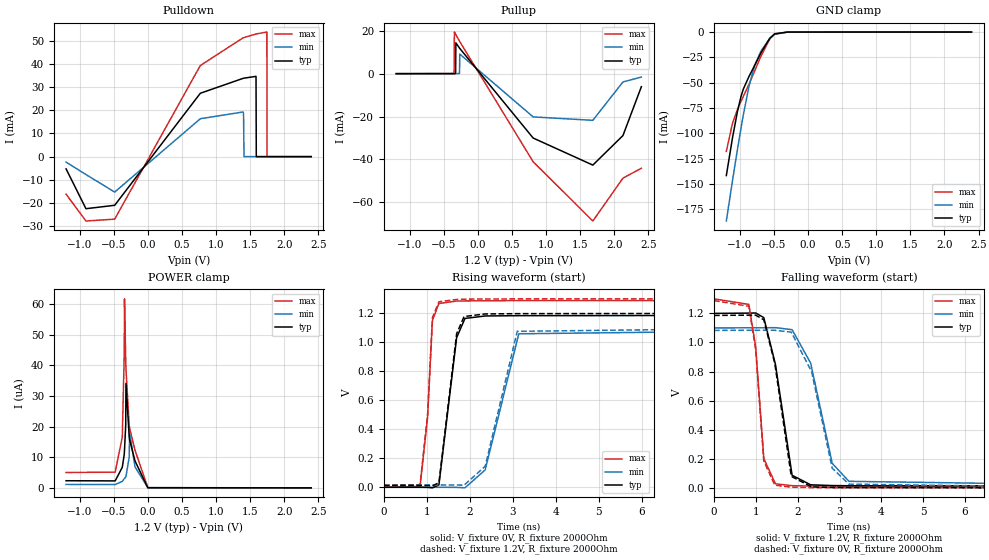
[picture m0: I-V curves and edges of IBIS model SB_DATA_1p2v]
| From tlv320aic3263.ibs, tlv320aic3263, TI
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|   SB_DATA_1p2v
[Model]   SB_DATA_1p2v
Model_type   I/O
Polarity   Non-Inverting
Enable   Active-Low
Vinl = 0.12
Vinh = 1.08
Vmeas = 0.6
Vref = 1.2
Cref = 1pF
Rref = 2000
|   typ   min   max
C_comp   0.971pF   0.938pF   1.010pF
[Voltage Range]   1.2   1.1   1.3
[Temperature Range]   27   125   -40
[Pullup Reference]   1.2   1.1   1.3
[Pulldown Reference]   -0   -0   -0
[Power Clamp Reference]   1.2   1.1   1.3
[GND Clamp Reference]   -0   -0   -0
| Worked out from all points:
|   slope of the pulldown table from 0 to 0.18 V, typ, clamps not added: 22.5 ohm
|   slope of the pullup table from 0 to 0.18 V, typ, clamps not added: 23.8 ohm
|   GND clamp passes 1 mA (typ) near -0.46 V on its own axis
|   falling waveform, V_fixture 1.2V, R_fixture 2000Ohm: 20-80 % time 294ps typ, 478ps min, 197ps max; typ from 1.2 V to 0.013 V
|   rising waveform, V_fixture 0V, R_fixture 2000Ohm: 20-80 % time 232ps typ, 382ps min, 162ps max; typ from 0 V to 1.19 V
|   rising waveform, V_fixture 1.2V, R_fixture 2000Ohm: 20-80 % time 230ps typ, 370ps min, 163ps max; typ from 0.013 V to 1.2 V
|   falling waveform, V_fixture 0V, R_fixture 2000Ohm: 20-80 % time 294ps typ, 478ps min, 197ps max; typ from 1.19 V to 0 V
[Pulldown]
|   Voltage   I(typ)   I(min)   I(max)
-1.2V     -5.286mA   -2.37mA    -16.2mA
-908.4mV  -22.46mA   -7.727mA   -27.77mA
-487.2mV  -20.99mA   -15.29mA   -26.97mA
769.2mV   27.34mA    16.35mA    39.31mA
1.396V    33.76mA    19.27mA    51.24mA
1.403V    33.81mA    18.59mA    51.31mA
1.41V     33.86mA    -859.3nA   51.38mA
1.586V    34.63mA    1.645nA    52.9mA
1.59V     -3.127uA   1.642nA    52.93mA
1.745V    197.2pA    1.618nA    53.75mA
1.748V    197.1pA    1.618nA    -614.5nA
2.396V    305.9pA    1.888nA    30.17pA
[GND Clamp]
|   Voltage   I(typ)   I(min)   I(max)
-1.2V     -141.7mA   -186.6mA   -117.8mA
-1.11V    -104.6mA   -146.9mA   -90.22mA
-1.038V   -78.75mA   -116.3mA   -76.61mA
-984mV    -63.46mA   -94.55mA   -68.36mA
-951.6mV  -56.47mA   -82.15mA   -63.64mA
-868.8mV  -44.01mA   -53.94mA   -51.7mA
-786mV    -33.17mA   -33.23mA   -38.76mA
-692.4mV  -20.56mA   -18.79mA   -23.91mA
-562.8mV  -6.154mA   -6.26mA    -6.871mA
-490.8mV  -1.797mA   -2.277mA   -1.795mA
-300mV    -21.89uA   -35.95uA   -26.81uA
2.396V    0A         0A         0A
[Pullup]
|   Voltage   I(typ)   I(min)   I(max)
-1.2V     842.9pA    8.701nA    61.33pA
-357.6mV  4.164uA    259.4nA    104uA
-350.4mV  8.121uA    257nA      521.9uA
-346.8mV  11.56uA    266.3nA    19.42mA
-328.8mV  130.7uA    482.1nA    18.39mA
-325.2mV  14.39mA    580.8nA    18.19mA
-271.2mV  11.94mA    78.29uA    15.14mA
-267.6mV  11.78mA    9.138mA    14.94mA
808.8mV   -30.02mA   -20.17mA   -41.09mA
1.684V    -42.64mA   -21.76mA   -68.72mA
2.126V    -28.86mA   -3.859mA   -48.72mA
2.396V    -6.07mA    -1.585mA   -44.12mA
[POWER Clamp]
|   Voltage   I(typ)   I(min)   I(max)
-1.2V     2.322uA    1.118uA    5.019uA
-480mV    2.269uA    1.068uA    5.127uA
-375.6mV  6.708uA    2.108uA    16.58uA
-346.8mV  10.94uA    3.003uA    43.76uA
-343.2mV  12.32uA    3.078uA    61.73uA
-325.2mV  20.51uA    3.543uA    41.71uA
-321.6mV  34.15uA    3.679uA    38.83uA
-274.8mV  16.92uA    9.923uA    20.56uA
-267.6mV  15.65uA    17.89uA    19.39uA
-188.4mV  8.757uA    6.849uA    12.27uA
-1.2mV    43.68nA    37.44nA    66.53nA
2.396V    0A         0A         0A
[Ramp]
R_load = 2000
|   typ   min   max
dV/dt_r   0.711726/2.31825e-10   0.650025/3.82476e-10   0.772994/1.62415e-10
dV/dt_f   0.712107/2.93834e-10   0.650031/4.76288e-10   0.773381/1.97433e-10
[Falling Waveform]
V_fixture = 1.2V
V_fixture_min = 1.1V
V_fixture_max = 1.3V
R_fixture = 2000Ohm
C_fixture = 0F
|   Time   V(typ)   V(min)   V(max)
0s        1.2V       1.1V       1.3V
831.2ps   1.202V     1.101V     1.262V
993.9ps   1.203V     1.101V     971.1mV
1.189ns   1.171V     1.101V     202mV
1.467ns   849.7mV    1.102V     27.8mV
1.866ns   86.29mV    1.088V     15.01mV
2.31ns    20.9mV     857.6mV    12.36mV
2.825ns   15.71mV    168.3mV    12.27mV
3.224ns   14.64mV    44.88mV    12.2mV
10ns      13.15mV    16.61mV    11.03mV
[Rising Waveform]
V_fixture = 0V
V_fixture_min = 0V
V_fixture_max = 0V
R_fixture = 2000Ohm
C_fixture = 0F
|   Time   V(typ)   V(min)   V(max)
0s        14.18nV    317.2nV    2.937nV
840.9ps   56.1uV     16.18uV    6.209mV
1.016ns   -435.4uV   19.5uV     483.4mV
1.129ns   -3.751mV   21.63uV    1.152V
1.28ns    16.48mV    24.46uV    1.268V
1.693ns   1.033V     -521.2uV   1.285V
1.887ns   1.165V     -3.484mV   1.286V
2.358ns   1.182V     120.2mV    1.287V
3.14ns    1.184V     1.059V     1.288V
10ns      1.186V     1.083V     1.288V
[Rising Waveform]
V_fixture = 1.2V
V_fixture_min = 1.1V
V_fixture_max = 1.3V
R_fixture = 2000Ohm
C_fixture = 0F
|   Time   V(typ)   V(min)   V(max)
0s        12.91mV    16.41mV    10.85mV
840.9ps   12.94mV    16.43mV    18.17mV
1.016ns   12.56mV    16.43mV    502mV
1.129ns   10.03mV    16.44mV    1.17V
1.28ns    31.59mV    16.44mV    1.28V
1.693ns   1.06V      15.94mV    1.296V
1.866ns   1.178V     14.61mV    1.298V
2.358ns   1.196V     145.4mV    1.299V
3.104ns   1.198V     1.076V     1.3V
10ns      1.2V       1.1V       1.3V
[Falling Waveform]
|Gnd
V_fixture = 0V
V_fixture_min = 0V
V_fixture_max = 0V
R_fixture = 2000Ohm
C_fixture = 0F
|   Time   V(typ)   V(min)   V(max)
0s        1.186V     1.083V     1.288V
831.2ps   1.188V     1.084V     1.249V
993.9ps   1.188V     1.084V     952mV
1.189ns   1.156V     1.084V     184.7mV
1.451ns   856.8mV    1.084V     18.62mV
1.846ns   78.91mV    1.071V     4.131mV
2.334ns   6.476mV    797.1mV    1.454mV
2.825ns   2.627mV    135mV      666.6uV
3.224ns   1.662mV    25.43mV    629.7uV
10ns      6.089uV    43.17uV    1.937uV
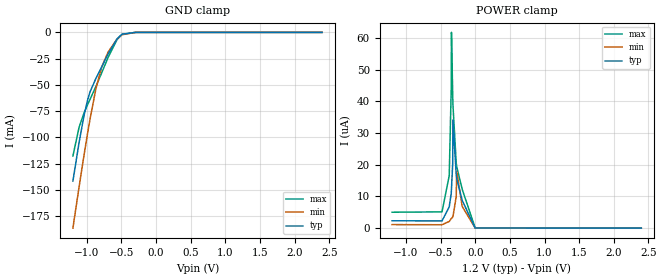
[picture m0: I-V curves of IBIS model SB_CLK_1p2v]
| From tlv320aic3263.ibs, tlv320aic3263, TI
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|   SB_CLK_1p2v
[Model]   SB_CLK_1p2v
Model_type   Input
Vinl = 0.12
Vinh = 1.08
|   typ   min   max
C_comp   0.971pF   0.938pF   1.010pF
[Voltage Range]   1.2   1.1   1.3
[Temperature Range]   27   125   -40
[Power Clamp Reference]   1.2   1.1   1.3
[GND Clamp Reference]   -0   -0   -0
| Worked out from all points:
|   GND clamp passes 1 mA (typ) near -0.46 V on its own axis
[GND Clamp]
|   Voltage   I(typ)   I(min)   I(max)
-1.2V     -141.7mA   -186.6mA   -117.8mA
-1.11V    -104.6mA   -146.9mA   -90.22mA
-1.038V   -78.75mA   -116.3mA   -76.61mA
-984mV    -63.46mA   -94.55mA   -68.36mA
-951.6mV  -56.47mA   -82.15mA   -63.64mA
-868.8mV  -44.01mA   -53.94mA   -51.7mA
-786mV    -33.17mA   -33.23mA   -38.76mA
-692.4mV  -20.56mA   -18.79mA   -23.91mA
-562.8mV  -6.154mA   -6.26mA    -6.871mA
-490.8mV  -1.797mA   -2.277mA   -1.795mA
-300mV    -21.89uA   -35.95uA   -26.81uA
2.396V    0A         0A         0A
[POWER Clamp]
|   Voltage   I(typ)   I(min)   I(max)
-1.2V     2.322uA    1.118uA    5.019uA
-480mV    2.269uA    1.068uA    5.127uA
-375.6mV  6.708uA    2.108uA    16.58uA
-346.8mV  10.94uA    3.003uA    43.76uA
-343.2mV  12.32uA    3.078uA    61.73uA
-325.2mV  20.51uA    3.543uA    41.71uA
-321.6mV  34.15uA    3.679uA    38.83uA
-274.8mV  16.92uA    9.923uA    20.56uA
-267.6mV  15.65uA    17.89uA    19.39uA
-188.4mV  8.757uA    6.849uA    12.27uA
-1.2mV    43.68nA    37.44nA    66.53nA
2.396V    0A         0A         0A
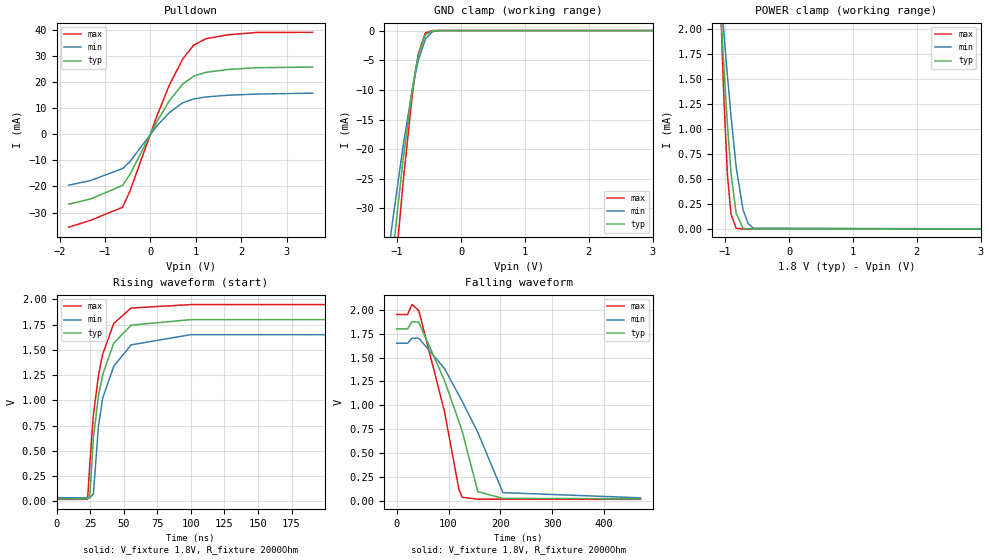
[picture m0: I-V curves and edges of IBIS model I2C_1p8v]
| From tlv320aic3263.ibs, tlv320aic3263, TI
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|   I2C_1p8v
[Model]   I2C_1p8v
Model_type   I/O_open_drain
Polarity   Non-Inverting
Enable   Active-High
Vinl = 0.54
Vinh = 1.26
Vmeas = 0.9
Vref = 0
Cref = 5pF
Rref = 2000
|   typ   min   max
C_comp   1.274pF   1.219pF   1.333pF
[Voltage Range]   1.8   1.65   1.95
[Temperature Range]   27   125   -40
[Pullup Reference]   1.8   1.65   1.95
[Pulldown Reference]   -0   -0   -0
[Power Clamp Reference]   1.8   1.65   1.95
[GND Clamp Reference]   -0   -0   -0
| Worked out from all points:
|   slope of the pulldown table from 0 to 0.27 V, typ, clamps not added: 31.1 ohm
|   GND clamp passes 1 mA (typ) near -0.57 V on its own axis
|   POWER clamp passes 1 mA (typ) near -0.96 V on its own axis
|   falling waveform, V_fixture 1.8V, R_fixture 2000Ohm: 20-80 % time 64.8ns typ, 85.6ns min, 48.8ns max; typ from 1.8 V to 0.026 V
|   rising waveform, V_fixture 1.8V, R_fixture 2000Ohm: 20-80 % time 12.4ns typ, 13.1ns min, 11.6ns max; typ from 0.026 V to 1.8 V
[Pulldown]
|   Voltage   I(typ)   I(min)   I(max)
-1.8V     -26.76mA   -19.51mA   -35.56mA
-1.314V   -24.77mA   -17.71mA   -32.93mA
-612mV    -19.57mA   -13.11mA   -27.94mA
-450mV    -15.35mA   -10.44mA   -21.73mA
144mV     4.818mA    3.184mA    7.002mA
414mV     12.69mA    8.219mA    18.67mA
711mV     19.14mA    11.99mA    28.75mA
954mV     22.19mA    13.48mA    34.04mA
1.224V    23.66mA    14.24mA    36.51mA
1.71V     24.74mA    14.9mA     38mA
2.331V    25.42mA    15.32mA    38.9mA
3.573V    25.65mA    15.7mA     38.95mA
[GND Clamp]
|   Voltage   I(typ)   I(min)   I(max)
-1.8V     -123mA     -98.92mA   -147.1mA
-1.233V   -55.18mA   -45.69mA   -66.35mA
-1.152V   -46.3mA    -38.73mA   -55.62mA
-1.071V   -37.73mA   -32.02mA   -45.21mA
-909mV    -21.87mA   -19.56mA   -25.73mA
-774mV    -10.65mA   -10.57mA   -11.84mA
-720mV    -6.977mA   -7.51mA    -7.33mA
-666mV    -3.998mA   -4.894mA   -3.785mA
-558mV    -694.3uA   -1.399mA   -419.1uA
-450mV    -48.22uA   -206.7uA   -14.05uA
-342mV    -1.744uA   -19.11uA   -162.1nA
3.573V    0A         0A         0A
[POWER Clamp]
|   Voltage   I(typ)   I(min)   I(max)
-1.8V     11.43mA    8.594mA    18.45mA
-1.098V   2.511mA    2.581mA    2.77mA
-1.071V   2.196mA    2.363mA    2.24mA
-1.044V   1.888mA    2.148mA    1.734mA
-1.017V   1.589mA    1.937mA    1.267mA
-963mV    1.031mA    1.525mA    530.8uA
-909mV    565.4uA    1.135mA    151.2uA
-828mV    156.4uA    622.8uA    6.725uA
-720mV    7.866uA    192.4uA    28.68nA
-639mV    432nA      52.31uA    0A
-558mV    5.887nA    8.012uA    0A
3.573V    0A         0A         0A
[Ramp]
R_load = 2000
|   typ   min   max
dV/dt_r   1.06459/1.23354e-008  0.968864/1.30945e-008   1.15843/1.1561e-008
dV/dt_f   1.06459/6.47139e-008  0.968864/8.5515e-008   1.15843/4.8731e-008
[Falling Waveform]
V_fixture = 1.8V
V_fixture_min = 1.65V
V_fixture_max = 1.95V
R_fixture = 2000Ohm
C_fixture = 0F
|   Time   V(typ)   V(min)   V(max)
0s        1.8V       1.65V      1.95V
21.06ns   1.799V     1.649V     1.949V
29.6ns    1.876V     1.703V     2.054V
42.59ns   1.869V     1.703V     1.991V
92.22ns   1.261V     1.385V     936.7mV
120.2ns   828.1mV    1.105V     118mV
126.3ns   729.9mV    1.042V     40.5mV
156.5ns   98.7mV     718.1mV    21.23mV
204.8ns   28.65mV    89.11mV    20.25mV
470ns     25.68mV    35.22mV    19.28mV
[Rising Waveform]
V_fixture = 1.8V
V_fixture_min = 1.65V
V_fixture_max = 1.95V
R_fixture = 2000Ohm
C_fixture = 0F
|   Time   V(typ)   V(min)   V(max)
0s        25.68mV    35.22mV    19.28mV
23.12ns   24.01mV    33.84mV    19.94mV
24.75ns   45.72mV    33.74mV    365.4mV
27.45ns   626.7mV    72.84mV    855.9mV
31.18ns   1.039V     741.1mV    1.243V
34.36ns   1.254V     1.021V     1.457V
42.59ns   1.567V     1.338V     1.762V
55.51ns   1.745V     1.55V      1.915V
99.87ns   1.8V       1.651V     1.949V
470ns     1.8V       1.65V      1.95V
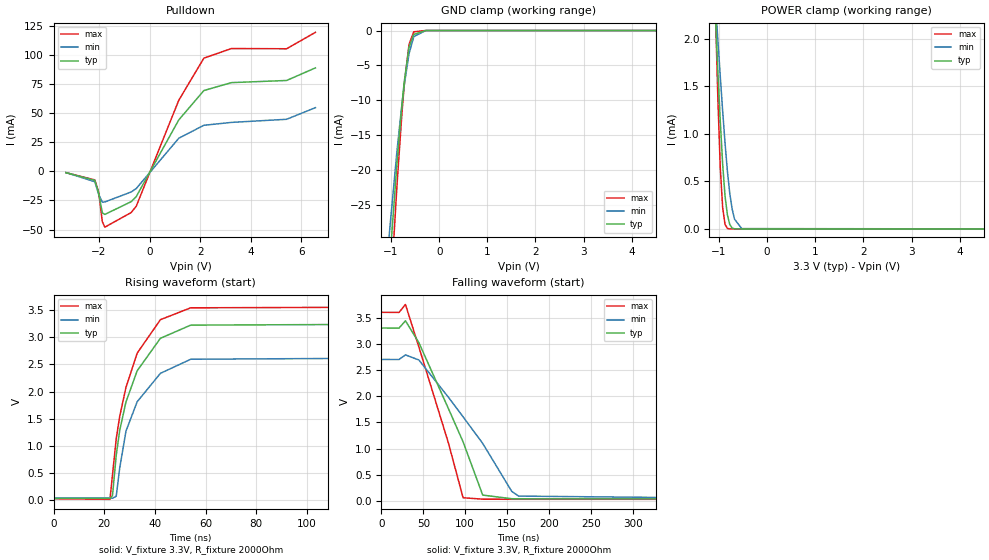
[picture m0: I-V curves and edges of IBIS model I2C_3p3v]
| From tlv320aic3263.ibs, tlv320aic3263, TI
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|   I2C_3p3v
[Model]   I2C_3p3v
Model_type   I/O_open_drain
Polarity   Non-Inverting
Enable   Active-High
Vinl = 0.8
Vinh = 2
Vmeas = 1.65
Vref = 0
Cref = 5pF
Rref = 2000
|   typ   min   max
C_comp   1.274pF   1.219pF   1.333pF
[Voltage Range]   3.3   2.7   3.6
[Temperature Range]   27   125   -40
[Pullup Reference]   3.3   2.7   3.6
[Pulldown Reference]   -0   -0   -0
[Power Clamp Reference]   3.3   2.7   3.6
[GND Clamp Reference]   -0   -0   -0
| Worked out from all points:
|   slope of the pulldown table from 0 to 0.495 V, typ, clamps not added: 24.4 ohm
|   GND clamp passes 1 mA (typ) near -0.57 V on its own axis
|   POWER clamp passes 1 mA (typ) near -0.96 V on its own axis
|   falling waveform, V_fixture 3.3V, R_fixture 2000Ohm: 20-80 % time 53.2ns typ, 71.6ns min, 40.6ns max; typ from 3.3 V to 0.038 V
|   rising waveform, V_fixture 3.3V, R_fixture 2000Ohm: 20-80 % time 11.5ns typ, 12.3ns min, 11.1ns max; typ from 0.038 V to 3.3 V
[Pulldown]
|   Voltage   I(typ)   I(min)   I(max)
-3.3V     -1.128mA   -1.068mA   -1.157mA
-2.162V   -7.775mA   -8.929mA   -7.348mA
-2.013V   -18.36mA   -19.59mA   -17.66mA
-1.865V   -35.63mA   -26.39mA   -43.24mA
-1.766V   -36.94mA   -26.26mA   -47.87mA
-726mV    -26.01mA   -17.71mA   -35.35mA
-528mV    -21.74mA   -14.81mA   -30.03mA
1.155V    44.12mA    28.4mA     60.99mA
2.145V    69.28mA    39.48mA    97.06mA
3.234V    76.07mA    41.96mA    105.3mA
5.412V    77.91mA    44.63mA    105.1mA
6.551V    88.71mA    54.61mA    119.2mA
[GND Clamp]
|   Voltage   I(typ)   I(min)   I(max)
-3.3V     -783.3mA   -712.9mA   -836mA
-1.221V   -53.85mA   -44.64mA   -64.75mA
-1.171V   -48.41mA   -40.38mA   -58.18mA
-1.122V   -43.08mA   -36.21mA   -51.73mA
-1.023V   -32.83mA   -28.18mA   -39.22mA
-874.5mV  -18.78mA   -17.11mA   -21.92mA
-775.5mV  -10.76mA   -10.66mA   -11.97mA
-726mV    -7.354mA   -7.83mA    -7.79mA
-627mV    -2.378mA   -3.342mA   -1.991mA
-528mV    -565.5uA   -877.2uA   -182.1uA
-280.5mV  -187.7nA   -4.182uA   -38.58nA
6.551V    0A         0A         0A
[POWER Clamp]
|   Voltage   I(typ)   I(min)   I(max)
-3.3V     31.29mA    21.97mA    53.42mA
-1.073V   2.213mA    2.375mA    2.269mA
-1.023V   1.654mA    1.983mA    1.366mA
-973.5mV  1.134mA    1.603mA    646.3uA
-924mV    681.5uA    1.24mA     225.7uA
-874.5mV  346.9uA    902.8uA    47.92uA
-825mV    147.4uA    606.3uA    5.86uA
-775.5mV  45.48uA    371.3uA    578.7nA
-726mV    9.636uA    207.9uA    29.35nA
-676.5mV  1.686uA    102.5uA    14.68nA
-528mV    8.133nA    3.647uA    0A
6.551V    0A         0A         0A
[Ramp]
R_load = 2000
|   typ   min   max
dV/dt_r   1.9571/1.15492e-008   1.59273/1.22255e-008   2.14173/1.105e-008
dV/dt_f   1.9571/5.32399e-008   1.59274/7.15891e-008   2.14173/4.06284e-008
[Falling Waveform]
V_fixture = 3.3V
V_fixture_min = 2.7V
V_fixture_max = 3.6V
R_fixture = 2000Ohm
C_fixture = 0F
|   Time   V(typ)   V(min)   V(max)
0s        3.3V       2.7V       3.6V
20.96ns   3.298V     2.699V     3.598V
28.68ns   3.438V     2.787V     3.749V
44.73ns   3.019V     2.69V      2.936V
80.05ns   1.759V     1.977V     1.101V
97.47ns   1.128V     1.605V     61.17mV
120.9ns   111.4mV    1.098V     33.15mV
155.5ns   42.17mV    183.7mV    31.33mV
163.8ns   39.98mV    91.97mV    31.3mV
470ns     38.17mV    45.43mV    30.45mV
[Rising Waveform]
V_fixture = 3.3V
V_fixture_min = 2.7V
V_fixture_max = 3.6V
R_fixture = 2000Ohm
C_fixture = 0F
|   Time   V(typ)   V(min)   V(max)
0s        38.17mV    45.44mV    30.45mV
22.27ns   34.67mV    45.46mV    19.49mV
23.27ns   89.11mV    39.51mV    468.8mV
24.74ns   827.4mV    76.33mV    1.132V
26.12ns   1.286V     593.8mV    1.545V
28.57ns   1.807V     1.271V     2.074V
33.01ns   2.382V     1.813V     2.706V
42.18ns   2.979V     2.335V     3.321V
54.14ns   3.221V     2.594V     3.539V
470ns     3.3V       2.7V       3.6V
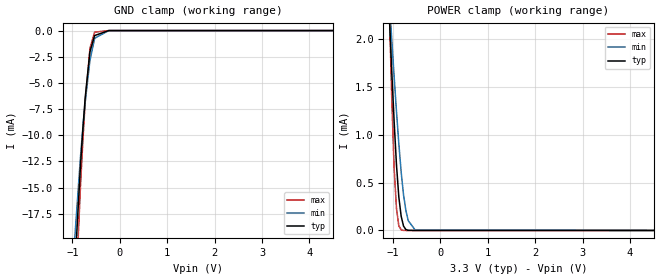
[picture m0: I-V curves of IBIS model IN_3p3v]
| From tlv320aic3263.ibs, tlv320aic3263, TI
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|   IN_3p3v
[Model]   IN_3p3v
Model_type   Input
Vinl = 0.99
Vinh = 2.31
|   typ   min   max
C_comp   1.095pF   1.082pF   1.133pF
[Voltage Range]   3.3   2.7   3.6
[Temperature Range]   27   125   -40
[Power Clamp Reference]   3.3   2.7   3.6
[GND Clamp Reference]   -0   -0   -0
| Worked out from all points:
|   GND clamp passes 1 mA (typ) near -0.58 V on its own axis
|   POWER clamp passes 1 mA (typ) near -0.96 V on its own axis
[GND Clamp]
|   Voltage   I(typ)   I(min)   I(max)
-3.3V     -782.9mA   -712.4mA   -835.6mA
-1.221V   -47.87mA   -39.35mA   -57.86mA
-1.171V   -42.98mA   -35.56mA   -51.94mA
-1.122V   -38.2mA    -31.85mA   -46.12mA
-1.023V   -29.01mA   -24.71mA   -34.85mA
-825mV    -12.75mA   -11.97mA   -14.69mA
-775.5mV  -9.352mA   -9.23mA    -10.46mA
-726mV    -6.355mA   -6.753mA   -6.753mA
-627mV    -2.02mA    -2.847mA   -1.688mA
-528mV    -475.3uA   -736.7uA   -151.8uA
-231mV    -15.95nA   -946.1nA   0A
6.551V    0A         0A         0A
[POWER Clamp]
|   Voltage   I(typ)   I(min)   I(max)
-3.3V     31.29mA    21.97mA    53.42mA
-1.073V   2.213mA    2.375mA    2.269mA
-1.023V   1.654mA    1.983mA    1.366mA
-973.5mV  1.134mA    1.603mA    646.3uA
-924mV    681.5uA    1.24mA     225.7uA
-874.5mV  346.9uA    902.8uA    47.94uA
-825mV    147.4uA    606.4uA    5.88uA
-775.5mV  45.5uA     371.3uA    598.4nA
-726mV    9.656uA    207.9uA    49.07nA
-676.5mV  1.706uA    102.5uA    24.53nA
-528mV    18.19nA    3.668uA    0A
6.551V    0A         0A         0A
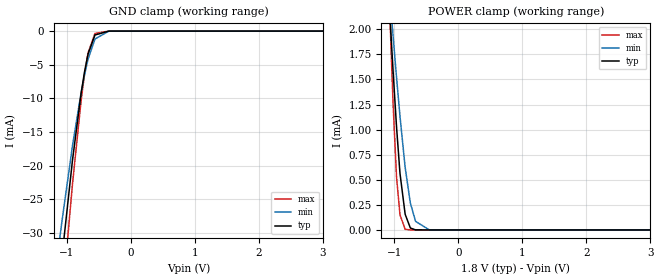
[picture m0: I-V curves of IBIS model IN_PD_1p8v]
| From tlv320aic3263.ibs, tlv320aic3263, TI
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|   IN_PD_1p8v
[Model]   IN_PD_1p8v
Model_type   Input
Vinl = 0.54
Vinh = 1.26
|   typ   min   max
C_comp   1.100pF   1.086pF   1.128pF
[Voltage Range]   1.8   1.65   1.95
[Temperature Range]   27   125   -40
[Power Clamp Reference]   1.8   1.65   1.95
[GND Clamp Reference]   -0   -0   -0
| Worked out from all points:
|   GND clamp passes 1 mA (typ) near -0.59 V on its own axis
|   POWER clamp passes 1 mA (typ) near -0.96 V on its own axis
[GND Clamp]
|   Voltage   I(typ)   I(min)   I(max)
-1.8V     -111mA     -88mA      -135mA
-1.26V    -51.79mA   -42.39mA   -62.59mA
-1.179V   -43.72mA   -36.13mA   -52.83mA
-1.125V   -38.49mA   -32.07mA   -46.46mA
-1.071V   -33.39mA   -28.12mA   -40.24mA
-909mV    -19.21mA   -17.07mA   -22.74mA
-774mV    -9.255mA   -9.15mA    -10.34mA
-720mV    -6.024mA   -6.473mA   -6.349mA
-666mV    -3.421mA   -4.192mA   -3.241mA
-558mV    -582.4uA   -1.18mA    -350.7uA
-342mV    -1.539uA   -15.95uA   -290.1nA
3.573V    0A         0A         0A
[POWER Clamp]
|   Voltage   I(typ)   I(min)   I(max)
-1.8V     11.43mA    8.594mA    18.45mA
-1.098V   2.511mA    2.581mA    2.77mA
-1.071V   2.196mA    2.363mA    2.24mA
-1.044V   1.888mA    2.148mA    1.734mA
-1.017V   1.589mA    1.937mA    1.267mA
-963mV    1.031mA    1.525mA    531.1uA
-909mV    565.5uA    1.135mA    151.4uA
-828mV    156.5uA    622.8uA    6.945uA
-747mV    19.42uA    269uA      365.4nA
-666mV    1.283uA    86.14uA    205.4nA
-450mV    100.5nA    505.3nA    201.5nA
3.573V    0A         0A         0A
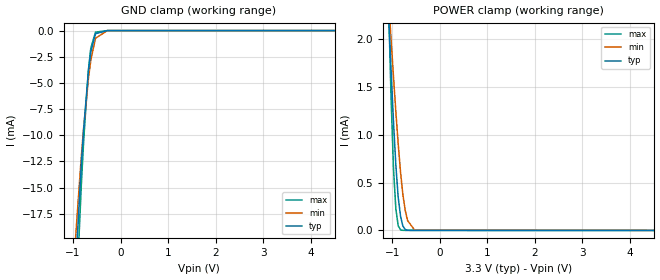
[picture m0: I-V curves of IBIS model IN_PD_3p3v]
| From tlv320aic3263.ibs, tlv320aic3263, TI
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|   EN_3p3v
[Model]   IN_PD_3p3v
Model_type   Input
Vinl = 0.99
Vinh = 2.31
|   typ   min   max
C_comp   1.100pF   1.086pF   1.128pF
[Voltage Range]   3.3   2.7   3.6
[Temperature Range]   27   125   -40
[Power Clamp Reference]   3.3   2.7   3.6
[GND Clamp Reference]   -0   -0   -0
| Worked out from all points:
|   GND clamp passes 1 mA (typ) near -0.58 V on its own axis
|   POWER clamp passes 1 mA (typ) near -0.96 V on its own axis
[GND Clamp]
|   Voltage   I(typ)   I(min)   I(max)
-3.3V     -782.9mA   -712.4mA   -835.6mA
-1.221V   -47.87mA   -39.35mA   -57.86mA
-1.171V   -42.98mA   -35.56mA   -51.94mA
-1.122V   -38.2mA    -31.85mA   -46.12mA
-1.023V   -29.01mA   -24.71mA   -34.85mA
-825mV    -12.75mA   -11.97mA   -14.69mA
-775.5mV  -9.352mA   -9.23mA    -10.46mA
-676.5mV  -3.871mA   -4.601mA   -3.763mA
-627mV    -2.02mA    -2.847mA   -1.689mA
-528mV    -299.1uA   -736.7uA   -152.2uA
-280.5mV  -280.3nA   -3.536uA   -207.1nA
6.551V    0A         0A         0A
[POWER Clamp]
|   Voltage   I(typ)   I(min)   I(max)
-3.3V     31.29mA    21.97mA    53.42mA
-1.073V   2.214mA    2.375mA    2.269mA
-1.023V   1.655mA    1.984mA    1.367mA
-973.5mV  1.134mA    1.603mA    647.2uA
-924mV    682uA      1.24mA     226.7uA
-874.5mV  347.4uA    903uA      48.91uA
-825mV    147.9uA    606.5uA    6.85uA
-775.5mV  45.99uA    371.5uA    1.57uA
-726mV    10.15uA    208.1uA    1.02uA
-676.5mV  2.201uA    102.7uA    964.5nA
-528mV    490.2nA    3.86uA     958.3nA
6.551V    0A         0A         0A
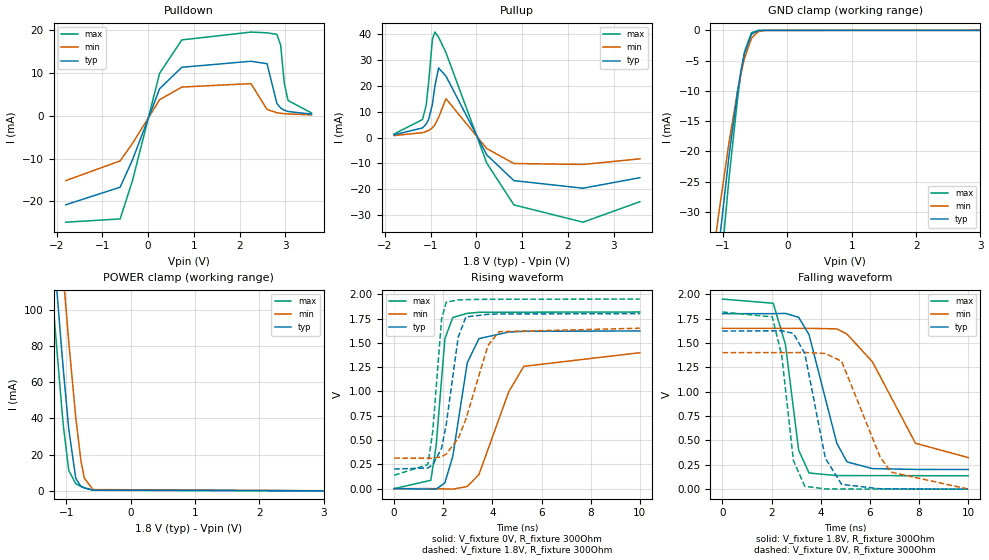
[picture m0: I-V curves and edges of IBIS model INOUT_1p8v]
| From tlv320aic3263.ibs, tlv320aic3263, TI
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|   INOUT_1p8v
[Model]   INOUT_1p8v
Model_type   I/O
Polarity   Non-Inverting
Enable   Active-High
Vinl = 0.54
Vinh = 1.26
Vmeas = 0.9
Vref = 0
Cref = 5pF
Rref = 10000
|   typ   min   max
C_comp   1.460pF   1.439pF   1.501pF
[Voltage Range]   1.8   1.65   1.95
[Temperature Range]   27   125   -40
[Pullup Reference]   1.8   1.65   1.95
[Pulldown Reference]   -0   -0   -0
[Power Clamp Reference]   1.8   1.65   1.95
[GND Clamp Reference]   -0   -0   -0
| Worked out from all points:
|   slope of the pulldown table from 0 to 0.27 V, typ, clamps not added: 40.3 ohm
|   slope of the pullup table from 0 to 0.27 V, typ, clamps not added: 34.5 ohm
|   GND clamp passes 1 mA (typ) near -0.58 V on its own axis
|   POWER clamp passes 1 mA (typ) near -0.66 V on its own axis
|   falling waveform, V_fixture 1.8V, R_fixture 300Ohm: 20-80 % time 889ps typ, 1.63ns min, 554ps max; typ from 1.8 V to 0.201 V
|   rising waveform, V_fixture 0V, R_fixture 300Ohm: 20-80 % time 598ps typ, 1.19ns min, 348ps max; typ from 0 V to 1.62 V
|   rising waveform, V_fixture 1.8V, R_fixture 300Ohm: 20-80 % time 536ps typ, 972ps min, 333ps max; typ from 0.201 V to 1.8 V
|   falling waveform, V_fixture 0V, R_fixture 300Ohm: 20-80 % time 719ps typ, 1.19ns min, 482ps max; typ from 1.62 V to 0 V
[Pulldown]
|   Voltage   I(typ)   I(min)   I(max)
-1.8V     -20.81mA   -15.15mA   -24.89mA
-612mV    -16.7mA    -10.54mA   -24.13mA
-342mV    -10.29mA   -6.449mA   -15.17mA
252mV     6.369mA    3.786mA    9.978mA
738mV     11.38mA    6.749mA    17.79mA
2.25V     12.79mA    7.557mA    19.62mA
2.601V    12.22mA    1.501mA    19.45mA
2.817V    2.895mA    733.5uA    19.08mA
2.898V    1.845mA    610.1uA    16.6mA
2.979V    1.328mA    521.1uA    7.614mA
3.06V     1.03mA     454.1uA    3.609mA
3.573V    413.7uA    247.9uA    687uA
[GND Clamp]
|   Voltage   I(typ)   I(min)   I(max)
-1.8V     -119.2mA   -95.35mA   -142.9mA
-1.26V    -56.01mA   -46.07mA   -67.41mA
-1.152V   -44.48mA   -37.07mA   -53.5mA
-1.071V   -36.18mA   -30.6mA    -43.41mA
-909mV    -20.86mA   -18.61mA   -24.59mA
-774mV    -10.08mA   -9.991mA   -11.22mA
-720mV    -6.574mA   -7.076mA   -6.911mA
-666mV    -3.743mA   -4.59mA    -3.54mA
-558mV    -640.1uA   -1.296mA   -385.5uA
-450mV    -44.19uA   -189.7uA   -12.87uA
-342mV    -1.601uA   -17.52uA   -152.1nA
3.573V    0A         0A         0A
[Pullup]
|   Voltage   I(typ)   I(min)   I(max)
-1.8V     1.094mA    756.7uA    1.395mA
-1.179V   3.72mA     1.905mA    6.969mA
-1.098V   5.255mA    2.354mA    12.69mA
-1.044V   7.093mA    2.783mA    21.62mA
-963mV    12.89mA    3.78mA     38.05mA
-909mV    19.89mA    4.869mA    40.81mA
-828mV    26.9mA     7.79mA     38.83mA
-666mV    23.76mA    15.04mA    32.83mA
225mV     -6.687mA   -4.26mA    -9.844mA
819mV     -16.67mA   -10.05mA   -26.06mA
2.331V    -19.6mA    -10.41mA   -32.75mA
3.573V    -15.53mA   -8.233mA   -24.83mA
[POWER Clamp]
|   Voltage   I(typ)   I(min)   I(max)
-1.8V     418.5mA    470.2mA    386.6mA
-1.26V    161.1mA    213.9mA    128.1mA
-1.233V   148.7mA    201.4mA    115.7mA
-1.179V   124.1mA    176.7mA    91.27mA
-1.071V   76.62mA    128.3mA    45.22mA
-1.044V   65.31mA    116.5mA    34.87mA
-963mV    34.04mA    82.11mA    11.31mA
-855mV    7.009mA    40.64mA    3.99mA
-774mV    2.438mA    16.61mA    2.53mA
-720mV    1.603mA    6.926mA    1.735mA
-585mV    449.6uA    745.8uA    374.5uA
3.573V    0A         0A         0A
[Ramp]
R_load = 300
|   typ   min   max
dV/dt_r   0.97338/5.97144e-010  0.838957/1.18531e-009   1.09014/3.46661e-010
dV/dt_f   0.959139/8.84584e-010  0.795582/1.62198e-009   1.08743/5.52783e-010
[Falling Waveform]
V_fixture = 1.8V
V_fixture_min = 1.65V
V_fixture_max = 1.95V
R_fixture = 300Ohm
C_fixture = 0F
|   Time   V(typ)   V(min)   V(max)
0s        1.8V       1.65V      1.95V
2.066ns   1.8V       1.65V      1.907V
2.562ns   1.803V     1.65V      1.484V
3.1ns     1.763V     1.65V      401.3mV
3.523ns   1.585V     1.65V      165.6mV
4.653ns   471.4mV    1.644V     139.3mV
5.071ns   279.3mV    1.59V      139.2mV
6.105ns   210.9mV    1.306V     138.8mV
7.856ns   202.5mV    471mV      138.3mV
10ns      201.4mV    324mV      137.6mV
[Rising Waveform]
V_fixture = 0V
V_fixture_min = 0V
V_fixture_max = 0V
R_fixture = 300Ohm
C_fixture = 0F
|   Time   V(typ)   V(min)   V(max)
0s        341.8nV    1.26uV     414.7nV
1.492ns   -5.101mV   520uV      85.56mV
1.707ns   -5.785mV   -453.5uV   433.8mV
2.066ns   59.41mV    -3.162mV   1.543V
2.386ns   330.3mV    -5.584mV   1.76V
2.978ns   1.296V     21.6mV     1.803V
3.452ns   1.543V     145.4mV    1.814V
4.668ns   1.611V     998.5mV    1.814V
5.28ns    1.618V     1.258V     1.815V
10ns      1.622V     1.398V     1.817V
[Rising Waveform]
V_fixture = 1.8V
V_fixture_min = 1.65V
V_fixture_max = 1.95V
R_fixture = 300Ohm
C_fixture = 0F
|   Time   V(typ)   V(min)   V(max)
0s        201.4mV    313.7mV    137.6mV
1.371ns   211.9mV    312mV      246.5mV
1.573ns   245.7mV    311.8mV    591.8mV
1.93ns    415.7mV    327.2mV    1.744V
2.121ns   660.8mV    356.1mV    1.918V
2.605ns   1.555V     514.7mV    1.941V
2.92ns    1.766V     714.3mV    1.944V
3.815ns   1.793V     1.47V      1.948V
4.263ns   1.797V     1.614V     1.948V
10ns      1.8V       1.65V      1.95V
[Falling Waveform]
|Gnd
V_fixture = 0V
V_fixture_min = 0V
V_fixture_max = 0V
R_fixture = 300Ohm
C_fixture = 0F
|   Time   V(typ)   V(min)   V(max)
0s        1.622V     1.4V       1.817V
2.027ns   1.624V     1.401V     1.767V
2.412ns   1.625V     1.401V     1.371V
2.887ns   1.598V     1.401V     293.9mV
3.351ns   1.392V     1.402V     29.5mV
4.187ns   317.1mV    1.392V     2.157mV
4.851ns   48.92mV    1.311V     1.91mV
6.419ns   3.795mV    328.4mV    1.329mV
6.863ns   3.326mV    174.5mV    1.164mV
10ns      8.216uV    1.372mV    15.19nV
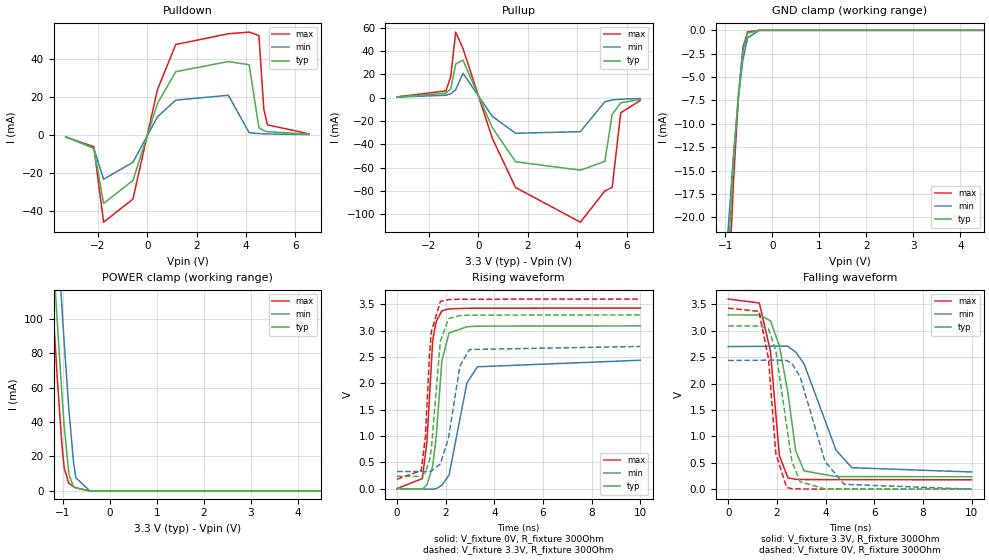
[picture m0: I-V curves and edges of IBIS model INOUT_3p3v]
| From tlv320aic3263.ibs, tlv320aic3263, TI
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|   INOUT_3p3v
[Model]   INOUT_3p3v
Model_type   I/O
Polarity   Non-Inverting
Enable   Active-High
Vinl = 0.99
Vinh = 2.31
Vmeas = 1.65
Vref = 0
Cref = 5pF
Rref = 10000
|   typ   min   max
C_comp   1.460pF   1.439pF   1.501pF
[Voltage Range]   3.3   2.7   3.6
[Temperature Range]   27   125   -40
[Pullup Reference]   3.3   2.7   3.6
[Pulldown Reference]   -0   -0   -0
[Power Clamp Reference]   3.3   2.7   3.6
[GND Clamp Reference]   -0   -0   -0
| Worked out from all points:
|   slope of the pulldown table from 0 to 0.495 V, typ, clamps not added: 25.6 ohm
|   slope of the pullup table from 0 to 0.495 V, typ, clamps not added: 21.4 ohm
|   GND clamp passes 1 mA (typ) near -0.58 V on its own axis
|   POWER clamp passes 1 mA (typ) near -0.66 V on its own axis
|   falling waveform, V_fixture 3.3V, R_fixture 300Ohm: 20-80 % time 600ps typ, 1.06ns min, 419ps max; typ from 3.3 V to 0.235 V
|   rising waveform, V_fixture 0V, R_fixture 300Ohm: 20-80 % time 325ps typ, 536ps min, 252ps max; typ from 0 V to 3.09 V
|   rising waveform, V_fixture 3.3V, R_fixture 300Ohm: 20-80 % time 311ps typ, 492ps min, 250ps max; typ from 0.235 V to 3.3 V
|   falling waveform, V_fixture 0V, R_fixture 300Ohm: 20-80 % time 539ps typ, 876ps min, 384ps max; typ from 3.09 V to 0 V
[Pulldown]
|   Voltage   I(typ)   I(min)   I(max)
-3.3V     -1.055mA   -906.4uA   -1.046mA
-2.162V   -6.852mA   -7.043mA   -6.178mA
-1.766V   -36.24mA   -23.41mA   -46.16mA
-577.5mV  -24.07mA   -14.44mA   -33.9mA
412.5mV   16.66mA    9.646mA    23.98mA
1.155V    33.54mA    18.47mA    47.93mA
3.284V    38.88mA    21.05mA    53.61mA
4.125V    37.2mA     1.25mA     54.5mA
4.521V    3.893mA    762.7uA    52.66mA
4.719V    2.305mA    636.9uA    13.53mA
4.867V    1.754mA    566.5uA    5.397mA
6.551V    463.3uA    249.9uA    622.9uA
[GND Clamp]
|   Voltage   I(typ)   I(min)   I(max)
-3.3V     -784.5mA   -714.4mA   -836.8mA
-1.221V   -51.79mA   -42.77mA   -62.34mA
-1.171V   -46.52mA   -38.66mA   -55.98mA
-1.122V   -41.36mA   -34.64mA   -49.73mA
-1.073V   -36.33mA   -30.71mA   -43.6mA
-1.023V   -31.44mA   -26.9mA    -37.62mA
-825mV    -13.87mA   -13.05mA   -15.92mA
-726mV    -6.933mA   -7.381mA   -7.35mA
-627mV    -2.214mA   -3.121mA   -1.85mA
-528mV    -328.8uA   -809.8uA   -167.1uA
-280.5mV  -180.1nA   -3.841uA   -51.83nA
6.551V    0A         0A         0A
[Pullup]
|   Voltage   I(typ)   I(min)   I(max)
-3.3V     596.2uA    442.9uA    673.5uA
-1.32V    3.756mA    2.079mA    5.759mA
-1.122V   7.52mA     3.243mA    18.16mA
-924mV    28.84mA    6.773mA    56.18mA
-627mV    32.18mA    20.93mA    42.17mA
561mV     -25.83mA   -16.01mA   -34.95mA
1.502V    -54.9mA    -30.54mA   -76.98mA
4.125V    -62.12mA   -29.14mA   -106.7mA
5.115V    -54.61mA   -3.488mA   -79.94mA
5.412V    -14.49mA   -1.977mA   -76.79mA
5.758V    -4.385mA   -1.297mA   -13.01mA
6.551V    -1.597mA   -718.8uA   -2.403mA
[POWER Clamp]
|   Voltage   I(typ)   I(min)   I(max)
-3.3V     1.155A     1.204A     1.126A
-1.27V    165.9mA    218.7mA    133mA
-1.221V   143.2mA    195.9mA    110.2mA
-1.171V   120.7mA    173.3mA    87.93mA
-1.122V   98.67mA    150.9mA    66.31mA
-1.023V   56.76mA    107.4mA    27.42mA
-973.5mV  37.78mA    86.45mA    13.4mA
-874.5mV  9.859mA    47.56mA    4.448mA
-775.5mV  2.47mA     16.97mA    2.554mA
-726mV    1.676mA    7.709mA    1.817mA
-429mV    22.89uA    75.31uA    7.664uA
6.551V    0A         0A         0A
[Ramp]
R_load = 300
|   typ   min   max
dV/dt_r   1.85482/3.22637e-010   1.46266/5.36251e-010   2.05706/2.51516e-010
dV/dt_f   1.83885/5.96403e-010   1.42465/1.04812e-009   2.05332/4.16244e-010
[Falling Waveform]
V_fixture = 3.3V
V_fixture_min = 2.7V
V_fixture_max = 3.6V
R_fixture = 300Ohm
C_fixture = 0F
|   Time   V(typ)   V(min)   V(max)
0s        3.3V       2.7V       3.6V
1.28ns    3.299V     2.705V     3.526V
1.735ns   3.19V      2.707V     2.611V
2.103ns   2.715V     2.708V     636.1mV
2.452ns   1.828V     2.707V     214.2mV
2.775ns   724.1mV    2.594V     187.4mV
3.119ns   344.9mV    2.371V     182.2mV
4.431ns   239mV      737.8mV    179.6mV
5.083ns   238.5mV    406.3mV    179.4mV
10ns      235.3mV    325.6mV    177.8mV
[Rising Waveform]
V_fixture = 0V
V_fixture_min = 0V
V_fixture_max = 0V
R_fixture = 300Ohm
C_fixture = 0F
|   Time   V(typ)   V(min)   V(max)
0s        540.1nV    1.189uV    290.1nV
1.043ns   -10.11mV   -6.732mV   191.3mV
1.232ns   71.62mV    -7.953mV   884.1mV
1.468ns   428.8mV    -9.475mV   2.815V
1.613ns   980.8mV    -1.123mV   3.173V
1.846ns   2.426V     64.71mV    3.376V
2.141ns   2.957V     258.1mV    3.414V
2.875ns   3.074V     2.006V     3.425V
3.303ns   3.086V     2.314V     3.426V
10ns      3.091V     2.438V     3.428V
[Rising Waveform]
V_fixture = 3.3V
V_fixture_min = 2.7V
V_fixture_max = 3.6V
R_fixture = 300Ohm
C_fixture = 0F
|   Time   V(typ)   V(min)   V(max)
0s        235.3mV    325.4mV    177.8mV
997ps     232.6mV    324.5mV    343.3mV
1.17ns    304.5mV    324.4mV    991.2mV
1.337ns   545.1mV    324.3mV    2.54V
1.413ns   750.8mV    332.5mV    2.98V
1.784ns   2.799V     468.9mV    3.554V
2.118ns   3.227V     962.5mV    3.59V
2.588ns   3.287V     2.33V      3.597V
2.983ns   3.294V     2.642V     3.597V
10ns      3.3V       2.7V       3.6V
[Falling Waveform]
|Gnd
V_fixture = 0V
V_fixture_min = 0V
V_fixture_max = 0V
R_fixture = 300Ohm
C_fixture = 0F
|   Time   V(typ)   V(min)   V(max)
0s        3.091V     2.438V     3.428V
1.264ns   3.091V     2.441V     3.367V
1.656ns   3.038V     2.442V     2.469V
1.956ns   2.626V     2.443V     677mV
2.398ns   1.208V     2.438V     34.46mV
2.621ns   518.8mV    2.376V     8.127mV
2.956ns   140.5mV    2.131V     3.954mV
3.976ns   3.978mV    526mV      1.831mV
4.761ns   3.46mV     92.21mV    1.593mV
10ns      1.497uV    103.5uV    53.58nV
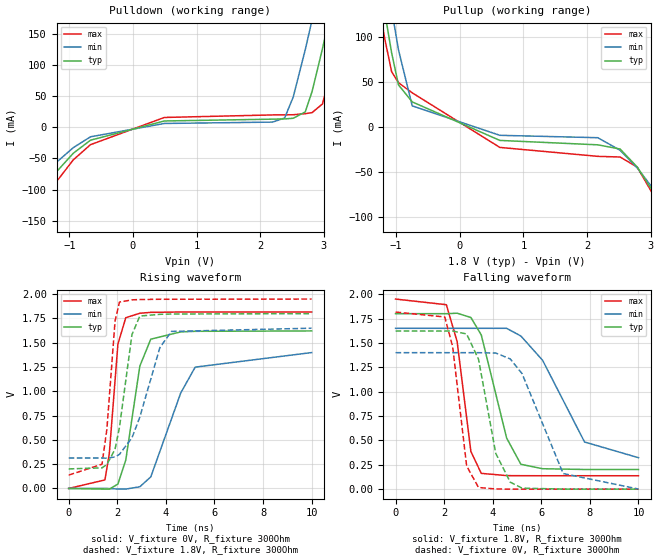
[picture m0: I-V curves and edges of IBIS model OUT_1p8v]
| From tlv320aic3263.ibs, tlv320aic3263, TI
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|   OUT_1p8v
[Model]   OUT_1p8v
Model_type   Output
Polarity   Non-Inverting
Vmeas = 0.9
Vref = 0
Cref = 5pF
Rref = 10000
|   typ   min   max
C_comp   1.397pF   1.384pF   1.430pF
[Voltage Range]   1.8   1.65   1.95
[Temperature Range]   27   125   -40
[Pullup Reference]   1.8   1.65   1.95
[Pulldown Reference]   -0   -0   -0
[Power Clamp Reference]   1.8   1.65   1.95
[GND Clamp Reference]   -0   -0   -0
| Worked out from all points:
|   slope of the pulldown table from 0 to 0.27 V, typ, clamps not added: 40.2 ohm
|   slope of the pullup table from 0 to 0.27 V, typ, clamps not added: 34.5 ohm
|   falling waveform, V_fixture 1.8V, R_fixture 300Ohm: 20-80 % time 877ps typ, 1.61ns min, 551ps max; typ from 1.8 V to 0.201 V
|   rising waveform, V_fixture 0V, R_fixture 300Ohm: 20-80 % time 587ps typ, 1.18ns min, 341ps max; typ from 0 V to 1.62 V
|   rising waveform, V_fixture 1.8V, R_fixture 300Ohm: 20-80 % time 526ps typ, 958ps min, 326ps max; typ from 0.201 V to 1.8 V
|   falling waveform, V_fixture 0V, R_fixture 300Ohm: 20-80 % time 726ps typ, 1.21ns min, 479ps max; typ from 1.62 V to 0 V
[Pulldown]
|   Voltage   I(typ)   I(min)   I(max)
-1.8V     -138.8mA   -109.5mA   -166.5mA
-936mV    -41.84mA   -32.85mA   -52.4mA
-666mV    -20.92mA   -15.49mA   -28.1mA
495mV     9.88mA     5.875mA    15.51mA
2.196V    12.8mA     8.08mA     19.59mA
2.385V    13.18mA    14.62mA    19.7mA
2.52V     14.23mA    48.22mA    19.89mA
2.709V    24.4mA     124mA      21.58mA
2.817V    57.26mA    172mA      23.35mA
2.979V    125.4mA    246.5mA    37.1mA
3.141V    199.6mA    322.7mA    98.87mA
3.573V    405.8mA    529.9mA    301.3mA
[Pullup]
|   Voltage   I(typ)   I(min)   I(max)
-1.8V     419.6mA    471mA      388mA
-1.287V   176.2mA    227.9mA    144.8mA
-1.233V   151.8mA    203.1mA    120.9mA
-1.179V   127.8mA    178.6mA    98.24mA
-1.071V   82.67mA    130.8mA    61.67mA
-963mV    46.93mA    85.89mA    49.36mA
-747mV    28.02mA    23.61mA    38.1mA
630mV     -14.75mA   -9.083mA   -22.51mA
2.169V    -19.64mA   -11.73mA   -32.44mA
2.52V     -24.3mA    -25.66mA   -33.17mA
2.79V     -44.36mA   -45.31mA   -44.43mA
3.573V    -129.9mA   -117.5mA   -140.2mA
[Ramp]
R_load = 300
|   typ   min   max
dV/dt_r   0.973382/5.86878e-010  0.839097/1.17645e-009   1.09014/3.4075e-010
dV/dt_f   0.959144/8.77181e-010  0.796362/1.6103e-009   1.08743/5.51104e-010
[Falling Waveform]
V_fixture = 1.8V
V_fixture_min = 1.65V
V_fixture_max = 1.95V
R_fixture = 300Ohm
C_fixture = 0F
|   Time   V(typ)   V(min)   V(max)
0s        1.8V       1.65V      1.95V
2.091ns   1.8V       1.65V      1.892V
2.535ns   1.805V     1.65V      1.514V
3.101ns   1.761V     1.65V      386.3mV
3.529ns   1.582V     1.65V      161.9mV
4.573ns   524.1mV    1.65V      139.3mV
5.159ns   255.3mV    1.571V     138.2mV
6.053ns   209.7mV    1.322V     137.7mV
7.78ns    201.9mV    483.9mV    137.7mV
10ns      201.4mV    322.7mV    137.6mV
[Rising Waveform]
V_fixture = 0V
V_fixture_min = 0V
V_fixture_max = 0V
R_fixture = 300Ohm
C_fixture = 0F
|   Time   V(typ)   V(min)   V(max)
0s        2.212nV    731.4nV    143.7pV
1.492ns   -6.66mV    529.8uV    87.97mV
1.673ns   -7.135mV   -896.9uV   360mV
2.027ns   45.53mV    -5.97mV    1.487V
2.351ns   292.9mV    -6.236mV   1.758V
2.929ns   1.26V      17.43mV    1.804V
3.38ns    1.537V     119.3mV    1.813V
4.611ns   1.612V     982mV      1.817V
5.207ns   1.618V     1.249V     1.817V
10ns      1.622V     1.399V     1.817V
[Rising Waveform]
V_fixture = 1.8V
V_fixture_min = 1.65V
V_fixture_max = 1.95V
R_fixture = 300Ohm
C_fixture = 0F
|   Time   V(typ)   V(min)   V(max)
0s        201.4mV    313.7mV    137.6mV
1.371ns   212.2mV    314mV      249.3mV
1.573ns   247mV      311.5mV    609.3mV
1.909ns   404mV      324.9mV    1.724V
2.091ns   630mV      351.7mV    1.919V
2.605ns   1.584V     521.8mV    1.942V
2.929ns   1.775V     734.5mV    1.945V
3.755ns   1.793V     1.451V     1.948V
4.232ns   1.796V     1.617V     1.948V
10ns      1.8V       1.65V      1.95V
[Falling Waveform]
|Gnd
V_fixture = 0V
V_fixture_min = 0V
V_fixture_max = 0V
R_fixture = 300Ohm
C_fixture = 0F
|   Time   V(typ)   V(min)   V(max)
0s        1.622V     1.4V       1.817V
2.027ns   1.622V     1.4V       1.766V
2.351ns   1.622V     1.4V       1.462V
2.926ns   1.592V     1.4V       238.2mV
3.416ns   1.332V     1.4V       17.05mV
4.126ns   366.5mV    1.396V     1.869mV
4.722ns   71.65mV    1.336V     614.1uV
5.207ns   10.76mV    1.185V     295.2uV
6.899ns   615.1uV    160.3mV    82.92uV
10ns      4.807uV    1.301mV    -249.9nV
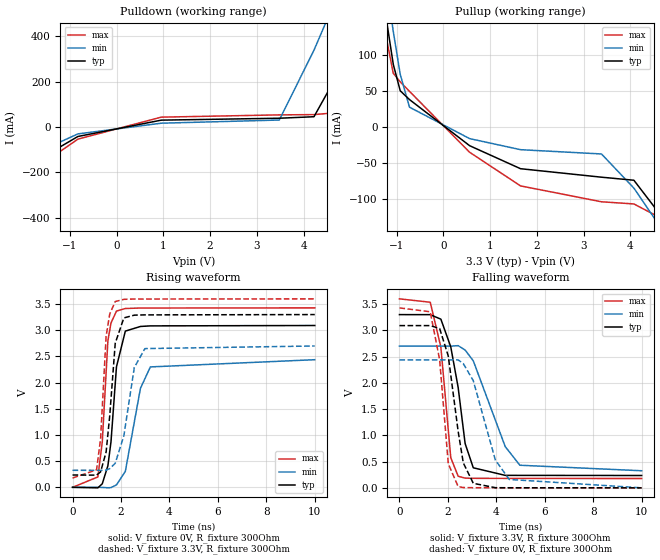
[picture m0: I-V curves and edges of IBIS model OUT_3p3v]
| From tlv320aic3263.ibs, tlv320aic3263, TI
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|   OUT_3p3v
[Model]   OUT_3p3v
Model_type   Output
Polarity   Non-Inverting
Vmeas = 1.65
Vref = 0
Cref = 5pF
Rref = 10000
|   typ   min   max
C_comp   1.397pF   1.384pF   1.430pF
[Voltage Range]   3.3   2.7   3.6
[Temperature Range]   27   125   -40
[Pullup Reference]   3.3   2.7   3.6
[Pulldown Reference]   -0   -0   -0
[Power Clamp Reference]   3.3   2.7   3.6
[GND Clamp Reference]   -0   -0   -0
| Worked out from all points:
|   slope of the pulldown table from 0 to 0.495 V, typ, clamps not added: 25.7 ohm
|   slope of the pullup table from 0 to 0.495 V, typ, clamps not added: 21.4 ohm
|   falling waveform, V_fixture 3.3V, R_fixture 300Ohm: 20-80 % time 593ps typ, 1.04ns min, 416ps max; typ from 3.3 V to 0.235 V
|   rising waveform, V_fixture 0V, R_fixture 300Ohm: 20-80 % time 320ps typ, 533ps min, 251ps max; typ from 0 V to 3.09 V
|   rising waveform, V_fixture 3.3V, R_fixture 300Ohm: 20-80 % time 307ps typ, 483ps min, 246ps max; typ from 0.235 V to 3.3 V
|   falling waveform, V_fixture 0V, R_fixture 300Ohm: 20-80 % time 531ps typ, 873ps min, 383ps max; typ from 3.09 V to 0 V
[Pulldown]
|   Voltage   I(typ)   I(min)   I(max)
-3.3V     -785.5mA   -715.2mA   -837.9mA
-2.805V   -544.7mA   -477.1mA   -595.4mA
-2.458V   -379.4mA   -315.5mA   -428.1mA
-1.964V   -178.6mA   -136.4mA   -215.3mA
-825mV    -41.39mA   -30.08mA   -53.04mA
957mV     30.52mA    17.08mA    43.78mA
3.482V    39mA       31.04mA    53.76mA
4.224V    45.6mA     339mA      54.94mA
4.62V     191.9mA    528.9mA    61.97mA
5.066V    403.1mA    745.5mA    227.8mA
5.313V    523.1mA    866.6mA    346.1mA
6.551V    1.131A     1.476A     953.2mA
[Pullup]
|   Voltage   I(typ)   I(min)   I(max)
-3.3V     1.156A     1.204A     1.126A
-1.27V    170.3mA    221mA      140mA
-1.073V   87.05mA    132.7mA    74.61mA
-924mV    50.3mA     73.15mA    62.74mA
-726mV    38.12mA    27.6mA     49.52mA
561mV     -25.83mA   -16.01mA   -34.95mA
1.65V     -57.73mA   -31.35mA   -81.57mA
3.382V    -69.5mA    -37.3mA    -103.6mA
4.075V    -73.72mA   -84.63mA   -106.6mA
4.67V     -124mA     -141.3mA   -126.8mA
4.867V    -146mA     -193mA     -149.2mA
6.551V    -761.8mA   -983.9mA   -667.4mA
[Ramp]
R_load = 300
|   typ   min   max
dV/dt_r   1.85483/3.19087e-010   1.46267/5.31098e-010   2.05706/2.50482e-010
dV/dt_f   1.83885/5.92512e-010   1.42466/1.04049e-009   2.05332/4.15546e-010
[Falling Waveform]
V_fixture = 3.3V
V_fixture_min = 2.7V
V_fixture_max = 3.6V
R_fixture = 300Ohm
C_fixture = 0F
|   Time   V(typ)   V(min)   V(max)
0s        3.3V       2.7V       3.6V
1.272ns   3.299V     2.7V       3.536V
1.711ns   3.213V     2.7V       2.681V
2.119ns   2.686V     2.699V     574.8mV
2.424ns   1.913V     2.709V     220.6mV
2.712ns   843.9mV    2.625V     185mV
3.049ns   382.1mV    2.42V      181.5mV
4.368ns   237.8mV    785.2mV    180mV
4.972ns   237.5mV    430.9mV    179.8mV
10ns      235.3mV    325.6mV    177.8mV
[Rising Waveform]
V_fixture = 0V
V_fixture_min = 0V
V_fixture_max = 0V
R_fixture = 300Ohm
C_fixture = 0F
|   Time   V(typ)   V(min)   V(max)
0s        1.919nV    188.7nV    -651.2pV
1.045ns   -9.994mV   861.5uV    198.2mV
1.227ns   67.96mV    -2.168mV   865.8mV
1.459ns   413.2mV    -8.238mV   2.803V
1.587ns   870.1mV    -5.288mV   3.139V
1.813ns   2.302V     45.85mV    3.367V
2.179ns   2.984V     305.4mV    3.416V
2.803ns   3.073V     1.891V     3.425V
3.212ns   3.084V     2.3V       3.425V
10ns      3.091V     2.438V     3.428V
[Rising Waveform]
V_fixture = 3.3V
V_fixture_min = 2.7V
V_fixture_max = 3.6V
R_fixture = 300Ohm
C_fixture = 0F
|   Time   V(typ)   V(min)   V(max)
0s        235.3mV    325.4mV    177.8mV
990.3ps   232.6mV    324.5mV    333.5mV
1.157ns   294.7mV    324.4mV    927.5mV
1.385ns   672.8mV    329mV      2.883V
1.534ns   1.362V     356.8mV    3.309V
1.762ns   2.752V     459.3mV    3.549V
2.118ns   3.236V     984.6mV    3.591V
2.549ns   3.289V     2.288V     3.597V
2.987ns   3.294V     2.65V      3.597V
10ns      3.3V       2.7V       3.6V
[Falling Waveform]
|Gnd
V_fixture = 0V
V_fixture_min = 0V
V_fixture_max = 0V
R_fixture = 300Ohm
C_fixture = 0F
|   Time   V(typ)   V(min)   V(max)
0s        3.091V     2.438V     3.428V
1.272ns   3.091V     2.438V     3.354V
1.66ns    3.035V     2.438V     2.439V
2.017ns   2.51V      2.437V     459.3mV
2.424ns   1.077V     2.438V     24.05mV
2.636ns   476.4mV    2.367V     6.272mV
3.049ns   86.55mV    2.041V     2.712mV
3.959ns   3.014mV    531.2mV    1.663mV
4.534ns   1.857mV    160mV      1.505mV
10ns      1.054uV    100.1uV    -61.09nV
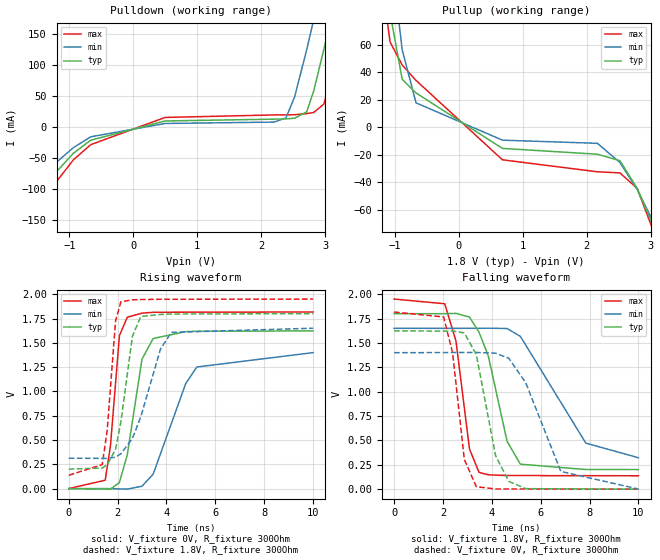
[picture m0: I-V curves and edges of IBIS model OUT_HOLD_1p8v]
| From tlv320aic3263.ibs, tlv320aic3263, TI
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|   OUT_HOLD_1p8v
[Model]   OUT_HOLD_1p8v
Model_type   Output
Polarity   Non-Inverting
Vmeas = 0.9
Vref = 0
Cref = 5pF
Rref = 10000
|   typ   min   max
C_comp   1.444pF   1.430pF   1.479pF
[Voltage Range]   1.8   1.65   1.95
[Temperature Range]   27   125   -40
[Pullup Reference]   1.8   1.65   1.95
[Pulldown Reference]   -0   -0   -0
[Power Clamp Reference]   1.8   1.65   1.95
[GND Clamp Reference]   -0   -0   -0
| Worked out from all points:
|   slope of the pulldown table from 0 to 0.27 V, typ, clamps not added: 40.1 ohm
|   slope of the pullup table from 0 to 0.27 V, typ, clamps not added: 34.4 ohm
|   falling waveform, V_fixture 1.8V, R_fixture 300Ohm: 20-80 % time 887ps typ, 1.62ns min, 552ps max; typ from 1.8 V to 0.201 V
|   rising waveform, V_fixture 0V, R_fixture 300Ohm: 20-80 % time 592ps typ, 1.19ns min, 344ps max; typ from 0 V to 1.62 V
|   rising waveform, V_fixture 1.8V, R_fixture 300Ohm: 20-80 % time 531ps typ, 966ps min, 329ps max; typ from 0.201 V to 1.8 V
|   falling waveform, V_fixture 0V, R_fixture 300Ohm: 20-80 % time 717ps typ, 1.18ns min, 481ps max; typ from 1.62 V to 0 V
[Pulldown]
|   Voltage   I(typ)   I(min)   I(max)
-1.8V     -138.9mA   -109.6mA   -166.7mA
-936mV    -41.92mA   -32.9mA    -52.51mA
-666mV    -20.99mA   -15.53mA   -28.19mA
495mV     9.917mA    5.896mA    15.57mA
2.196V    12.83mA    8.112mA    19.62mA
2.385V    13.23mA    14.76mA    19.75mA
2.52V     14.29mA    48.5mA     19.96mA
2.709V    24.56mA    124.3mA    21.67mA
2.817V    57.49mA    172.3mA    23.45mA
2.979V    125.7mA    246.8mA    37.27mA
3.141V    199.9mA    323mA      99.07mA
3.573V    406.1mA    530.3mA    301.5mA
[Pullup]
|   Voltage   I(typ)   I(min)   I(max)
-1.8V     419.8mA    471.3mA    388.2mA
-1.287V   176.5mA    228.2mA    145mA
-1.233V   152mA      203.4mA    121.1mA
-1.179V   128mA      178.9mA    98.43mA
-1.071V   82.9mA     131.1mA    61.83mA
-882mV    34.69mA    56.2mA     45.17mA
-666mV    24.86mA    17.67mA    33.97mA
684mV     -15.45mA   -9.46mA    -23.73mA
2.169V    -19.68mA   -11.76mA   -32.46mA
2.52V     -24.37mA   -25.71mA   -33.25mA
2.79V     -44.44mA   -45.38mA   -44.54mA
3.573V    -130mA     -117.7mA   -140.4mA
[Ramp]
R_load = 300
|   typ   min   max
dV/dt_r   0.973593/5.91078e-010  0.839281/1.18558e-009   1.0903/3.42594e-010
dV/dt_f   0.959547/8.86694e-010  0.796559/1.62324e-009   1.08769/5.52397e-010
[Falling Waveform]
V_fixture = 1.8V
V_fixture_min = 1.65V
V_fixture_max = 1.95V
R_fixture = 300Ohm
C_fixture = 0F
|   Time   V(typ)   V(min)   V(max)
0s        1.8V       1.65V      1.95V
2.074ns   1.8V       1.65V      1.902V
2.535ns   1.803V     1.65V      1.518V
3.088ns   1.765V     1.65V      411.2mV
3.479ns   1.609V     1.65V      171.8mV
3.857ns   1.366V     1.651V     147mV
4.626ns   489.9mV    1.648V     139.9mV
5.171ns   256.4mV    1.567V     139.6mV
7.848ns   201.5mV    472.5mV    138.3mV
10ns      200.8mV    322.4mV    137.2mV
[Rising Waveform]
V_fixture = 0V
V_fixture_min = 0V
V_fixture_max = 0V
R_fixture = 300Ohm
C_fixture = 0F
|   Time   V(typ)   V(min)   V(max)
0s        338.6nV    2.714uV    23.4nV
1.492ns   -5.092mV   525.4uV    86.43mV
1.707ns   -5.756mV   -424.8uV   439.7mV
2.074ns   63.37mV    -3.152mV   1.574V
2.395ns   347.3mV    -5.531mV   1.763V
2.998ns   1.332V     24.56mV    1.805V
3.454ns   1.544V     148.2mV    1.814V
4.786ns   1.615V     1.08V      1.815V
5.239ns   1.618V     1.251V     1.815V
10ns      1.623V     1.399V     1.817V
[Rising Waveform]
V_fixture = 1.8V
V_fixture_min = 1.65V
V_fixture_max = 1.95V
R_fixture = 300Ohm
C_fixture = 0F
|   Time   V(typ)   V(min)   V(max)
0s        200.7mV    312.6mV    137.2mV
1.371ns   211.3mV    310.9mV    246.6mV
1.573ns   245.3mV    310.7mV    596.4mV
1.917ns   405.4mV    324.5mV    1.727V
2.135ns   687.9mV    358.2mV    1.922V
2.605ns   1.566V     515.7mV    1.942V
2.946ns   1.771V     737.3mV    1.945V
3.76ns    1.792V     1.439V     1.948V
4.203ns   1.796V     1.608V     1.948V
10ns      1.8V       1.65V      1.95V
[Falling Waveform]
|Gnd
V_fixture = 0V
V_fixture_min = 0V
V_fixture_max = 0V
R_fixture = 300Ohm
C_fixture = 0F
|   Time   V(typ)   V(min)   V(max)
0s        1.623V     1.4V       1.817V
2.029ns   1.622V     1.401V     1.766V
2.395ns   1.623V     1.402V     1.398V
2.876ns   1.603V     1.402V     304.6mV
3.366ns   1.38V      1.402V     25.27mV
4.155ns   343.2mV    1.395V     1.845mV
4.695ns   80.13mV    1.343V     1.675mV
5.39ns    5.575mV    1.091V     1.455mV
6.825ns   3.193mV    182mV      1.002mV
10ns      7.952uV    1.314mV    -200.9nV
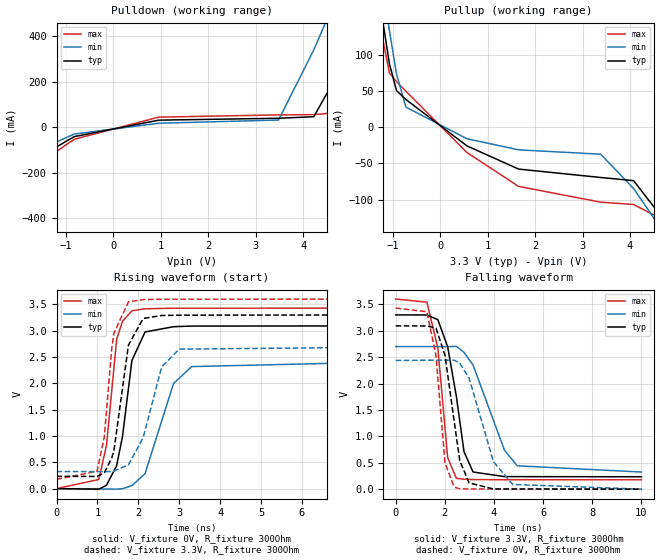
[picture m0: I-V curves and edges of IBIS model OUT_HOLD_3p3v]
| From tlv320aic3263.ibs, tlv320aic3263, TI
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|   OUT_HOLD_3p3v
[Model]   OUT_HOLD_3p3v
Model_type   Output
Polarity   Non-Inverting
Vmeas = 1.65
Vref = 0
Cref = 5pF
Rref = 10000
|   typ   min   max
C_comp   1.444pF   1.430pF   1.479pF
[Voltage Range]   3.3   2.7   3.6
[Temperature Range]   27   125   -40
[Pullup Reference]   3.3   2.7   3.6
[Pulldown Reference]   -0   -0   -0
[Power Clamp Reference]   3.3   2.7   3.6
[GND Clamp Reference]   -0   -0   -0
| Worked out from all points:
|   slope of the pulldown table from 0 to 0.495 V, typ, clamps not added: 25.6 ohm
|   slope of the pullup table from 0 to 0.495 V, typ, clamps not added: 21.4 ohm
|   falling waveform, V_fixture 3.3V, R_fixture 300Ohm: 20-80 % time 596ps typ, 1.05ns min, 416ps max; typ from 3.3 V to 0.235 V
|   rising waveform, V_fixture 0V, R_fixture 300Ohm: 20-80 % time 322ps typ, 533ps min, 251ps max; typ from 0 V to 3.09 V
|   rising waveform, V_fixture 3.3V, R_fixture 300Ohm: 20-80 % time 310ps typ, 490ps min, 248ps max; typ from 0.235 V to 3.3 V
|   falling waveform, V_fixture 0V, R_fixture 300Ohm: 20-80 % time 535ps typ, 874ps min, 382ps max; typ from 3.09 V to 0 V
[Pulldown]
|   Voltage   I(typ)   I(min)   I(max)
-3.3V     -785.6mA   -715.4mA   -837.9mA
-2.805V   -544.8mA   -477.3mA   -595.5mA
-2.458V   -379.5mA   -315.6mA   -428.2mA
-1.964V   -178.8mA   -136.6mA   -215.6mA
-825mV    -41.49mA   -30.14mA   -53.18mA
957mV     30.63mA    17.14mA    43.94mA
3.482V    39.02mA    31.21mA    53.73mA
4.224V    45.74mA    339.4mA    55.02mA
4.62V     192.1mA    529.3mA    62.12mA
5.066V    403.4mA    745.9mA    228mA
5.313V    523.4mA    867mA      346.3mA
6.551V    1.131A     1.476A     953.4mA
[Pullup]
|   Voltage   I(typ)   I(min)   I(max)
-3.3V     1.156A     1.205A     1.127A
-1.27V    170.5mA    221.3mA    140.2mA
-1.073V   87.28mA    133mA      74.76mA
-924mV    50.42mA    73.43mA    62.86mA
-726mV    38.2mA     27.69mA    49.62mA
561mV     -25.88mA   -16.04mA   -35.02mA
1.65V     -57.86mA   -31.31mA   -81.76mA
3.382V    -69.49mA   -37.35mA   -103.5mA
4.075V    -73.82mA   -84.72mA   -106.7mA
4.67V     -124.1mA   -141.5mA   -127mA
4.867V    -146.1mA   -193.1mA   -149.4mA
6.551V    -761.9mA   -984mA     -667.5mA
[Ramp]
R_load = 300
|   typ   min   max
dV/dt_r   1.85506/3.20084e-010   1.46297/5.31383e-010   2.05724/2.49692e-010
dV/dt_f   1.83927/5.95467e-010   1.42527/1.04765e-009   2.05363/4.15561e-010
[Falling Waveform]
V_fixture = 3.3V
V_fixture_min = 2.7V
V_fixture_max = 3.6V
R_fixture = 300Ohm
C_fixture = 0F
|   Time   V(typ)   V(min)   V(max)
0s        3.3V       2.7V       3.6V
1.269ns   3.299V     2.7V       3.542V
1.716ns   3.209V     2.7V       2.673V
2.114ns   2.698V     2.699V     597.1mV
2.469ns   1.756V     2.704V     205.2mV
2.78ns    709.4mV    2.591V     188.7mV
3.148ns   325.3mV    2.35V      181.4mV
4.423ns   237.8mV    741.8mV    179.1mV
4.944ns   237.5mV    442.5mV    178.9mV
10ns      234.6mV    324.6mV    177.3mV
[Rising Waveform]
V_fixture = 0V
V_fixture_min = 0V
V_fixture_max = 0V
R_fixture = 300Ohm
C_fixture = 0F
|   Time   V(typ)   V(min)   V(max)
0s        935nV      2.272uV    453.8nV
1.033ns   -10.08mV   -6.718mV   173.3mV
1.222ns   63.04mV    -7.95mV    820.6mV
1.471ns   438.6mV    -9.57mV    2.837V
1.613ns   988.8mV    -1.045mV   3.179V
1.844ns   2.435V     57.18mV    3.377V
2.165ns   2.975V     284.7mV    3.416V
2.862ns   3.075V     1.998V     3.426V
3.306ns   3.087V     2.318V     3.426V
10ns      3.092V     2.438V     3.429V
[Rising Waveform]
V_fixture = 3.3V
V_fixture_min = 2.7V
V_fixture_max = 3.6V
R_fixture = 300Ohm
C_fixture = 0F
|   Time   V(typ)   V(min)   V(max)
0s        234.5mV    324.3mV    177.3mV
990.2ps   231.8mV    323.4mV    330.6mV
1.168ns   301.7mV    323.3mV    977.3mV
1.349ns   578.7mV    323.5mV    2.648V
1.404ns   723.6mV    333.7mV    2.953V
1.759ns   2.726V     453.8mV    3.547V
2.119ns   3.231V     969.1mV    3.59V
2.572ns   3.288V     2.312V     3.597V
3ns       3.294V     2.649V     3.597V
10ns      3.3V       2.7V       3.6V
[Falling Waveform]
|Gnd
V_fixture = 0V
V_fixture_min = 0V
V_fixture_max = 0V
R_fixture = 300Ohm
C_fixture = 0F
|   Time   V(typ)   V(min)   V(max)
0s        3.092V     2.438V     3.429V
1.269ns   3.091V     2.441V     3.36V
1.639ns   3.051V     2.442V     2.533V
2.005ns   2.538V     2.443V     500.9mV
2.382ns   1.28V      2.442V     38.07mV
2.608ns   538.9mV    2.384V     7.497mV
2.988ns   117.8mV    2.103V     2.755mV
3.979ns   4.099mV    518.6mV    2.366mV
4.762ns   3.567mV    89.6mV     2.059mV
10ns      3.274uV    107.3uV    767.7nV
